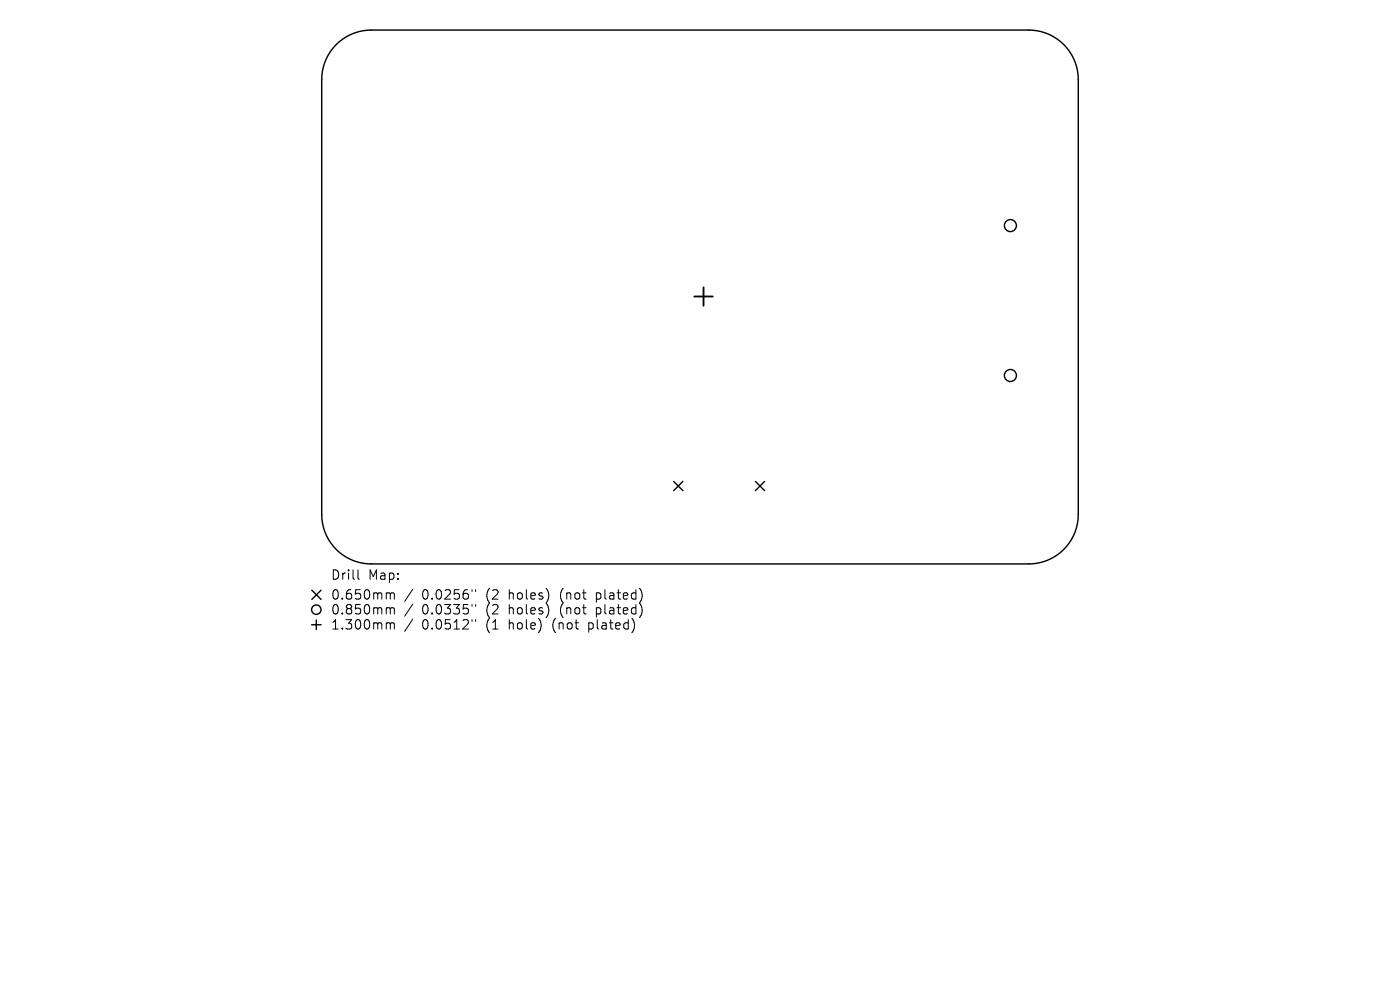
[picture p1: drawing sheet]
<svg xmlns="http://www.w3.org/2000/svg" width="297mm" height="210mm" viewBox="0 0 297 210" stroke-linecap="round" stroke-linejoin="round" font-family="sans-serif">
<defs><g id="words">
<g font-size="2.8">
<text x="70.1" y="123.3">Drill</text>
<text x="78.1" y="123.3">Map:</text>
<text x="70.1" y="127.5">0.650mm</text>
<text x="70.1" y="130.6">0.850mm</text>
<text x="89.5" y="127.5">0.0256&quot;</text>
<text x="89.5" y="130.6">0.0335&quot;</text>
<text x="103.3" y="127.5">(2</text>
<text x="103.3" y="130.6">(2</text>
<text x="108.2" y="127.5">holes)</text>
<text x="108.2" y="130.6">holes)</text>
<text x="119.3" y="127.5">(not</text>
<text x="119.3" y="130.6">(not</text>
<text x="127.1" y="127.5">plated)</text>
<text x="127.1" y="130.6">plated)</text>
<text x="70.1" y="133.8">1.300mm</text>
<text x="89.5" y="133.8">0.0512&quot;</text>
<text x="103.3" y="133.8">(1</text>
<text x="108.2" y="133.8">hole)</text>
<text x="117.7" y="133.8">(not</text>
<text x="125.5" y="133.8">plated)</text>
</g>
</g></defs>
<g fill="none" stroke="#000" stroke-width=".3">
<path d="M71.3 9.5a10.5 10.5 0 0 1 7.5-3.1h139.5a10.5 10.5 0 0 1 10.5 10.5v92.2a10.5 10.5 0 0 1-10.5 10.5h-139.5a10.5 10.5 0 0 1-10.5-10.5v-92.2a10.5 10.5 0 0 1 3-7.4zM142.9 102.1l2 2M144.9 102.1l-2 2M160.3 102.1l1.9 2M162.2 102.1l-1.9 2M66.1 132.5h2M66.2 125.2l1.9 2M67.1 131.5v2M68.1 125.2l-1.9 2"/>
<circle cx="214.4" cy="47.9" r="1.27"/>
<circle cx="214.4" cy="79.7" r="1.28"/>
<circle cx="67.1" cy="129.3" r="1"/>
</g>
<path d="M147.3 62.9h3.9M149.3 60.9v3.9" fill="none" stroke="#000" stroke-width=".39"/>
<g fill="none" stroke="#000" stroke-width=".21">
<path d="M75.9 120.9v1.7l.3 .3M82.2 125.8l.5 .1 .1 .1M82.2 128.9l.5 .1 .1 .2M82.2 132.1l.5 .1 .1 .2M82.8 126l.3-.2 .5 .1 .1 1.2M82.8 126v1.1M82.8 129.2v1M82.8 132.4v1M82.8 129.2l.3-.3 .5 .1 .1 1.2M82.8 132.4l.3-.3 .5 .1 .1 1.2M87.6 125l-1.7 2.6M87.6 128.1l-1.7 2.6"/>
<path d="M87.6 131.3l-1.7 2.6M100.1 125.1v.4M100.1 128.2v.4M100.1 131.4v.4M100.9 125.1v.4M100.9 128.2v.4M100.9 131.4v.4"/>
</g>
<use href="#words"/>
</svg>
